VERSION 5.8 ;
BUSBITCHARS "[]" ;
DIVIDERCHAR "/" ;
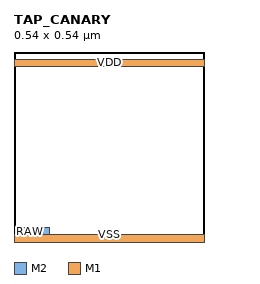
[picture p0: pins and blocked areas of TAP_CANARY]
MACRO TAP_CANARY
 CLASS BLOCK ;
 ORIGIN 0 0 ;
 SIZE 0.54 BY 0.54 ;
 SYMMETRY X Y ;
 PIN RAW
  DIRECTION INPUT ;
  USE CLOCK ;
  PORT
   LAYER M2 ;
    RECT 0.02 0.02 0.04 0.04 ;
  END
 END RAW
 PIN REF
  DIRECTION INPUT ;
  USE CLOCK ;
  PORT
   LAYER M2 ;
    RECT 0.08 0.02 0.10 0.04 ;
  END
 END REF
 PIN VDD
  DIRECTION INOUT ;
  USE POWER ;
  PORT
   LAYER M1 ;
    RECT 0 0.50 0.54 0.52 ;
  END
 END VDD
 PIN VSS
  DIRECTION INOUT ;
  USE GROUND ;
  PORT
   LAYER M1 ;
    RECT 0 0.00 0.54 0.02 ;
  END
 END VSS
END TAP_CANARY
END LIBRARY
